VERSION 5.7 ;
  NOWIREEXTENSIONATPIN ON ;
  DIVIDERCHAR "/" ;
  BUSBITCHARS "[]" ;
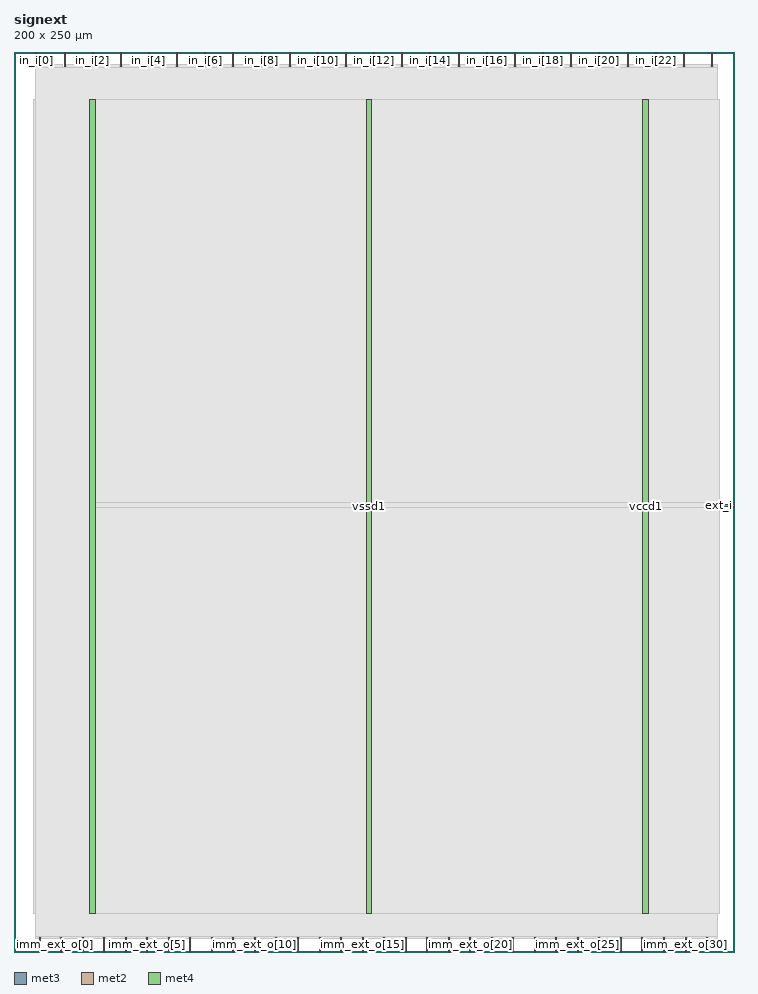
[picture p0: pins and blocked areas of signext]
MACRO signext
  CLASS BLOCK ;
  FOREIGN signext ;
  ORIGIN 0.000 0.000 ;
  SIZE 200.000 BY 250.000 ;
  PIN ext_i
    DIRECTION INPUT ;
    USE SIGNAL ;
    ANTENNAGATEAREA 0.196500 ;
    PORT
      LAYER met3 ;
        RECT 196.000 123.800 200.000 124.400 ;
    END
  END ext_i
  PIN imm_ext_o[0]
    DIRECTION OUTPUT TRISTATE ;
    USE SIGNAL ;
    ANTENNADIFFAREA 2.673000 ;
    PORT
      LAYER met2 ;
        RECT 6.990 0.000 7.270 4.000 ;
    END
  END imm_ext_o[0]
  PIN imm_ext_o[10]
    DIRECTION OUTPUT TRISTATE ;
    USE SIGNAL ;
    ANTENNADIFFAREA 2.673000 ;
    PORT
      LAYER met2 ;
        RECT 66.790 0.000 67.070 4.000 ;
    END
  END imm_ext_o[10]
  PIN imm_ext_o[11]
    DIRECTION OUTPUT TRISTATE ;
    USE SIGNAL ;
    ANTENNADIFFAREA 2.673000 ;
    PORT
      LAYER met2 ;
        RECT 72.770 0.000 73.050 4.000 ;
    END
  END imm_ext_o[11]
  PIN imm_ext_o[12]
    DIRECTION OUTPUT TRISTATE ;
    USE SIGNAL ;
    ANTENNADIFFAREA 2.673000 ;
    PORT
      LAYER met2 ;
        RECT 78.750 0.000 79.030 4.000 ;
    END
  END imm_ext_o[12]
  PIN imm_ext_o[13]
    DIRECTION OUTPUT TRISTATE ;
    USE SIGNAL ;
    ANTENNADIFFAREA 2.673000 ;
    PORT
      LAYER met2 ;
        RECT 84.730 0.000 85.010 4.000 ;
    END
  END imm_ext_o[13]
  PIN imm_ext_o[14]
    DIRECTION OUTPUT TRISTATE ;
    USE SIGNAL ;
    ANTENNADIFFAREA 2.673000 ;
    PORT
      LAYER met2 ;
        RECT 90.710 0.000 90.990 4.000 ;
    END
  END imm_ext_o[14]
  PIN imm_ext_o[15]
    DIRECTION OUTPUT TRISTATE ;
    USE SIGNAL ;
    ANTENNADIFFAREA 2.673000 ;
    PORT
      LAYER met2 ;
        RECT 96.690 0.000 96.970 4.000 ;
    END
  END imm_ext_o[15]
  PIN imm_ext_o[16]
    DIRECTION OUTPUT TRISTATE ;
    USE SIGNAL ;
    ANTENNADIFFAREA 2.673000 ;
    PORT
      LAYER met2 ;
        RECT 102.670 0.000 102.950 4.000 ;
    END
  END imm_ext_o[16]
  PIN imm_ext_o[17]
    DIRECTION OUTPUT TRISTATE ;
    USE SIGNAL ;
    ANTENNADIFFAREA 2.673000 ;
    PORT
      LAYER met2 ;
        RECT 108.650 0.000 108.930 4.000 ;
    END
  END imm_ext_o[17]
  PIN imm_ext_o[18]
    DIRECTION OUTPUT TRISTATE ;
    USE SIGNAL ;
    ANTENNADIFFAREA 2.673000 ;
    PORT
      LAYER met2 ;
        RECT 114.630 0.000 114.910 4.000 ;
    END
  END imm_ext_o[18]
  PIN imm_ext_o[19]
    DIRECTION OUTPUT TRISTATE ;
    USE SIGNAL ;
    ANTENNADIFFAREA 2.673000 ;
    PORT
      LAYER met2 ;
        RECT 120.610 0.000 120.890 4.000 ;
    END
  END imm_ext_o[19]
  PIN imm_ext_o[1]
    DIRECTION OUTPUT TRISTATE ;
    USE SIGNAL ;
    ANTENNADIFFAREA 2.673000 ;
    PORT
      LAYER met2 ;
        RECT 12.970 0.000 13.250 4.000 ;
    END
  END imm_ext_o[1]
  PIN imm_ext_o[20]
    DIRECTION OUTPUT TRISTATE ;
    USE SIGNAL ;
    ANTENNADIFFAREA 2.673000 ;
    PORT
      LAYER met2 ;
        RECT 126.590 0.000 126.870 4.000 ;
    END
  END imm_ext_o[20]
  PIN imm_ext_o[21]
    DIRECTION OUTPUT TRISTATE ;
    USE SIGNAL ;
    ANTENNADIFFAREA 2.673000 ;
    PORT
      LAYER met2 ;
        RECT 132.570 0.000 132.850 4.000 ;
    END
  END imm_ext_o[21]
  PIN imm_ext_o[22]
    DIRECTION OUTPUT TRISTATE ;
    USE SIGNAL ;
    ANTENNADIFFAREA 2.673000 ;
    PORT
      LAYER met2 ;
        RECT 138.550 0.000 138.830 4.000 ;
    END
  END imm_ext_o[22]
  PIN imm_ext_o[23]
    DIRECTION OUTPUT TRISTATE ;
    USE SIGNAL ;
    ANTENNADIFFAREA 2.673000 ;
    PORT
      LAYER met2 ;
        RECT 144.530 0.000 144.810 4.000 ;
    END
  END imm_ext_o[23]
  PIN imm_ext_o[24]
    DIRECTION OUTPUT TRISTATE ;
    USE SIGNAL ;
    ANTENNADIFFAREA 2.673000 ;
    PORT
      LAYER met2 ;
        RECT 150.510 0.000 150.790 4.000 ;
    END
  END imm_ext_o[24]
  PIN imm_ext_o[25]
    DIRECTION OUTPUT TRISTATE ;
    USE SIGNAL ;
    ANTENNADIFFAREA 2.673000 ;
    PORT
      LAYER met2 ;
        RECT 156.490 0.000 156.770 4.000 ;
    END
  END imm_ext_o[25]
  PIN imm_ext_o[26]
    DIRECTION OUTPUT TRISTATE ;
    USE SIGNAL ;
    ANTENNADIFFAREA 2.673000 ;
    PORT
      LAYER met2 ;
        RECT 162.470 0.000 162.750 4.000 ;
    END
  END imm_ext_o[26]
  PIN imm_ext_o[27]
    DIRECTION OUTPUT TRISTATE ;
    USE SIGNAL ;
    ANTENNADIFFAREA 2.673000 ;
    PORT
      LAYER met2 ;
        RECT 168.450 0.000 168.730 4.000 ;
    END
  END imm_ext_o[27]
  PIN imm_ext_o[28]
    DIRECTION OUTPUT TRISTATE ;
    USE SIGNAL ;
    ANTENNADIFFAREA 2.673000 ;
    PORT
      LAYER met2 ;
        RECT 174.430 0.000 174.710 4.000 ;
    END
  END imm_ext_o[28]
  PIN imm_ext_o[29]
    DIRECTION OUTPUT TRISTATE ;
    USE SIGNAL ;
    ANTENNADIFFAREA 2.673000 ;
    PORT
      LAYER met2 ;
        RECT 180.410 0.000 180.690 4.000 ;
    END
  END imm_ext_o[29]
  PIN imm_ext_o[2]
    DIRECTION OUTPUT TRISTATE ;
    USE SIGNAL ;
    ANTENNADIFFAREA 2.673000 ;
    PORT
      LAYER met2 ;
        RECT 18.950 0.000 19.230 4.000 ;
    END
  END imm_ext_o[2]
  PIN imm_ext_o[30]
    DIRECTION OUTPUT TRISTATE ;
    USE SIGNAL ;
    ANTENNADIFFAREA 2.673000 ;
    PORT
      LAYER met2 ;
        RECT 186.390 0.000 186.670 4.000 ;
    END
  END imm_ext_o[30]
  PIN imm_ext_o[31]
    DIRECTION OUTPUT TRISTATE ;
    USE SIGNAL ;
    ANTENNADIFFAREA 2.673000 ;
    PORT
      LAYER met2 ;
        RECT 192.370 0.000 192.650 4.000 ;
    END
  END imm_ext_o[31]
  PIN imm_ext_o[3]
    DIRECTION OUTPUT TRISTATE ;
    USE SIGNAL ;
    ANTENNADIFFAREA 2.673000 ;
    PORT
      LAYER met2 ;
        RECT 24.930 0.000 25.210 4.000 ;
    END
  END imm_ext_o[3]
  PIN imm_ext_o[4]
    DIRECTION OUTPUT TRISTATE ;
    USE SIGNAL ;
    ANTENNADIFFAREA 2.673000 ;
    PORT
      LAYER met2 ;
        RECT 30.910 0.000 31.190 4.000 ;
    END
  END imm_ext_o[4]
  PIN imm_ext_o[5]
    DIRECTION OUTPUT TRISTATE ;
    USE SIGNAL ;
    ANTENNADIFFAREA 2.673000 ;
    PORT
      LAYER met2 ;
        RECT 36.890 0.000 37.170 4.000 ;
    END
  END imm_ext_o[5]
  PIN imm_ext_o[6]
    DIRECTION OUTPUT TRISTATE ;
    USE SIGNAL ;
    ANTENNADIFFAREA 2.673000 ;
    PORT
      LAYER met2 ;
        RECT 42.870 0.000 43.150 4.000 ;
    END
  END imm_ext_o[6]
  PIN imm_ext_o[7]
    DIRECTION OUTPUT TRISTATE ;
    USE SIGNAL ;
    ANTENNADIFFAREA 2.673000 ;
    PORT
      LAYER met2 ;
        RECT 48.850 0.000 49.130 4.000 ;
    END
  END imm_ext_o[7]
  PIN imm_ext_o[8]
    DIRECTION OUTPUT TRISTATE ;
    USE SIGNAL ;
    ANTENNADIFFAREA 2.673000 ;
    PORT
      LAYER met2 ;
        RECT 54.830 0.000 55.110 4.000 ;
    END
  END imm_ext_o[8]
  PIN imm_ext_o[9]
    DIRECTION OUTPUT TRISTATE ;
    USE SIGNAL ;
    ANTENNADIFFAREA 2.673000 ;
    PORT
      LAYER met2 ;
        RECT 60.810 0.000 61.090 4.000 ;
    END
  END imm_ext_o[9]
  PIN imm_size_i[0]
    DIRECTION INPUT ;
    USE SIGNAL ;
    ANTENNAGATEAREA 0.213000 ;
    PORT
      LAYER met2 ;
        RECT 185.930 246.000 186.210 250.000 ;
    END
  END imm_size_i[0]
  PIN imm_size_i[1]
    DIRECTION INPUT ;
    USE SIGNAL ;
    ANTENNAGATEAREA 0.213000 ;
    PORT
      LAYER met2 ;
        RECT 193.750 246.000 194.030 250.000 ;
    END
  END imm_size_i[1]
  PIN in_i[0]
    DIRECTION INPUT ;
    USE SIGNAL ;
    ANTENNAGATEAREA 0.196500 ;
    PORT
      LAYER met2 ;
        RECT 6.070 246.000 6.350 250.000 ;
    END
  END in_i[0]
  PIN in_i[10]
    DIRECTION INPUT ;
    USE SIGNAL ;
    ANTENNAGATEAREA 0.196500 ;
    PORT
      LAYER met2 ;
        RECT 84.270 246.000 84.550 250.000 ;
    END
  END in_i[10]
  PIN in_i[11]
    DIRECTION INPUT ;
    USE SIGNAL ;
    ANTENNAGATEAREA 0.196500 ;
    PORT
      LAYER met2 ;
        RECT 92.090 246.000 92.370 250.000 ;
    END
  END in_i[11]
  PIN in_i[12]
    DIRECTION INPUT ;
    USE SIGNAL ;
    ANTENNAGATEAREA 0.213000 ;
    PORT
      LAYER met2 ;
        RECT 99.910 246.000 100.190 250.000 ;
    END
  END in_i[12]
  PIN in_i[13]
    DIRECTION INPUT ;
    USE SIGNAL ;
    ANTENNAGATEAREA 0.196500 ;
    PORT
      LAYER met2 ;
        RECT 107.730 246.000 108.010 250.000 ;
    END
  END in_i[13]
  PIN in_i[14]
    DIRECTION INPUT ;
    USE SIGNAL ;
    ANTENNAGATEAREA 0.196500 ;
    PORT
      LAYER met2 ;
        RECT 115.550 246.000 115.830 250.000 ;
    END
  END in_i[14]
  PIN in_i[15]
    DIRECTION INPUT ;
    USE SIGNAL ;
    ANTENNAGATEAREA 0.126000 ;
    PORT
      LAYER met2 ;
        RECT 123.370 246.000 123.650 250.000 ;
    END
  END in_i[15]
  PIN in_i[16]
    DIRECTION INPUT ;
    USE SIGNAL ;
    ANTENNAGATEAREA 0.196500 ;
    PORT
      LAYER met2 ;
        RECT 131.190 246.000 131.470 250.000 ;
    END
  END in_i[16]
  PIN in_i[17]
    DIRECTION INPUT ;
    USE SIGNAL ;
    ANTENNAGATEAREA 0.196500 ;
    PORT
      LAYER met2 ;
        RECT 139.010 246.000 139.290 250.000 ;
    END
  END in_i[17]
  PIN in_i[18]
    DIRECTION INPUT ;
    USE SIGNAL ;
    ANTENNAGATEAREA 0.196500 ;
    PORT
      LAYER met2 ;
        RECT 146.830 246.000 147.110 250.000 ;
    END
  END in_i[18]
  PIN in_i[19]
    DIRECTION INPUT ;
    USE SIGNAL ;
    ANTENNAGATEAREA 0.196500 ;
    PORT
      LAYER met2 ;
        RECT 154.650 246.000 154.930 250.000 ;
    END
  END in_i[19]
  PIN in_i[1]
    DIRECTION INPUT ;
    USE SIGNAL ;
    ANTENNAGATEAREA 0.196500 ;
    PORT
      LAYER met2 ;
        RECT 13.890 246.000 14.170 250.000 ;
    END
  END in_i[1]
  PIN in_i[20]
    DIRECTION INPUT ;
    USE SIGNAL ;
    ANTENNAGATEAREA 0.196500 ;
    PORT
      LAYER met2 ;
        RECT 162.470 246.000 162.750 250.000 ;
    END
  END in_i[20]
  PIN in_i[21]
    DIRECTION INPUT ;
    USE SIGNAL ;
    ANTENNAGATEAREA 0.196500 ;
    PORT
      LAYER met2 ;
        RECT 170.290 246.000 170.570 250.000 ;
    END
  END in_i[21]
  PIN in_i[22]
    DIRECTION INPUT ;
    USE SIGNAL ;
    ANTENNAGATEAREA 0.213000 ;
    PORT
      LAYER met2 ;
        RECT 178.110 246.000 178.390 250.000 ;
    END
  END in_i[22]
  PIN in_i[2]
    DIRECTION INPUT ;
    USE SIGNAL ;
    ANTENNAGATEAREA 0.196500 ;
    PORT
      LAYER met2 ;
        RECT 21.710 246.000 21.990 250.000 ;
    END
  END in_i[2]
  PIN in_i[3]
    DIRECTION INPUT ;
    USE SIGNAL ;
    ANTENNAGATEAREA 0.196500 ;
    PORT
      LAYER met2 ;
        RECT 29.530 246.000 29.810 250.000 ;
    END
  END in_i[3]
  PIN in_i[4]
    DIRECTION INPUT ;
    USE SIGNAL ;
    ANTENNAGATEAREA 0.196500 ;
    PORT
      LAYER met2 ;
        RECT 37.350 246.000 37.630 250.000 ;
    END
  END in_i[4]
  PIN in_i[5]
    DIRECTION INPUT ;
    USE SIGNAL ;
    ANTENNAGATEAREA 0.196500 ;
    PORT
      LAYER met2 ;
        RECT 45.170 246.000 45.450 250.000 ;
    END
  END in_i[5]
  PIN in_i[6]
    DIRECTION INPUT ;
    USE SIGNAL ;
    ANTENNAGATEAREA 0.196500 ;
    PORT
      LAYER met2 ;
        RECT 52.990 246.000 53.270 250.000 ;
    END
  END in_i[6]
  PIN in_i[7]
    DIRECTION INPUT ;
    USE SIGNAL ;
    ANTENNAGATEAREA 0.196500 ;
    PORT
      LAYER met2 ;
        RECT 60.810 246.000 61.090 250.000 ;
    END
  END in_i[7]
  PIN in_i[8]
    DIRECTION INPUT ;
    USE SIGNAL ;
    ANTENNAGATEAREA 0.196500 ;
    PORT
      LAYER met2 ;
        RECT 68.630 246.000 68.910 250.000 ;
    END
  END in_i[8]
  PIN in_i[9]
    DIRECTION INPUT ;
    USE SIGNAL ;
    ANTENNAGATEAREA 0.196500 ;
    PORT
      LAYER met2 ;
        RECT 76.450 246.000 76.730 250.000 ;
    END
  END in_i[9]
  PIN vccd1
    DIRECTION INOUT ;
    USE POWER ;
    PORT
      LAYER met4 ;
        RECT 21.040 10.640 22.640 236.880 ;
    END
    PORT
      LAYER met4 ;
        RECT 174.640 10.640 176.240 236.880 ;
    END
  END vccd1
  PIN vssd1
    DIRECTION INOUT ;
    USE GROUND ;
    PORT
      LAYER met4 ;
        RECT 97.840 10.640 99.440 236.880 ;
    END
  END vssd1
  OBS
      LAYER nwell ;
        RECT 5.330 235.225 194.310 236.830 ;
        RECT 5.330 229.785 194.310 232.615 ;
        RECT 5.330 224.345 194.310 227.175 ;
        RECT 5.330 218.905 194.310 221.735 ;
        RECT 5.330 213.465 194.310 216.295 ;
        RECT 5.330 208.025 194.310 210.855 ;
        RECT 5.330 202.585 194.310 205.415 ;
        RECT 5.330 197.145 194.310 199.975 ;
        RECT 5.330 191.705 194.310 194.535 ;
        RECT 5.330 186.265 194.310 189.095 ;
        RECT 5.330 180.825 194.310 183.655 ;
        RECT 5.330 175.385 194.310 178.215 ;
        RECT 5.330 169.945 194.310 172.775 ;
        RECT 5.330 164.505 194.310 167.335 ;
        RECT 5.330 159.065 194.310 161.895 ;
        RECT 5.330 153.625 194.310 156.455 ;
        RECT 5.330 148.185 194.310 151.015 ;
        RECT 5.330 142.745 194.310 145.575 ;
        RECT 5.330 137.305 194.310 140.135 ;
        RECT 5.330 131.865 194.310 134.695 ;
        RECT 5.330 126.425 194.310 129.255 ;
        RECT 5.330 120.985 194.310 123.815 ;
        RECT 5.330 115.545 194.310 118.375 ;
        RECT 5.330 110.105 194.310 112.935 ;
        RECT 5.330 104.665 194.310 107.495 ;
        RECT 5.330 99.225 194.310 102.055 ;
        RECT 5.330 93.785 194.310 96.615 ;
        RECT 5.330 88.345 194.310 91.175 ;
        RECT 5.330 82.905 194.310 85.735 ;
        RECT 5.330 77.465 194.310 80.295 ;
        RECT 5.330 72.025 194.310 74.855 ;
        RECT 5.330 66.585 194.310 69.415 ;
        RECT 5.330 61.145 194.310 63.975 ;
        RECT 5.330 55.705 194.310 58.535 ;
        RECT 5.330 50.265 194.310 53.095 ;
        RECT 5.330 44.825 194.310 47.655 ;
        RECT 5.330 39.385 194.310 42.215 ;
        RECT 5.330 33.945 194.310 36.775 ;
        RECT 5.330 28.505 194.310 31.335 ;
        RECT 5.330 23.065 194.310 25.895 ;
        RECT 5.330 17.625 194.310 20.455 ;
        RECT 5.330 12.185 194.310 15.015 ;
      LAYER li1 ;
        RECT 5.520 10.795 194.120 236.725 ;
      LAYER met1 ;
        RECT 5.520 10.640 195.430 236.880 ;
      LAYER met2 ;
        RECT 6.630 245.720 13.610 246.570 ;
        RECT 14.450 245.720 21.430 246.570 ;
        RECT 22.270 245.720 29.250 246.570 ;
        RECT 30.090 245.720 37.070 246.570 ;
        RECT 37.910 245.720 44.890 246.570 ;
        RECT 45.730 245.720 52.710 246.570 ;
        RECT 53.550 245.720 60.530 246.570 ;
        RECT 61.370 245.720 68.350 246.570 ;
        RECT 69.190 245.720 76.170 246.570 ;
        RECT 77.010 245.720 83.990 246.570 ;
        RECT 84.830 245.720 91.810 246.570 ;
        RECT 92.650 245.720 99.630 246.570 ;
        RECT 100.470 245.720 107.450 246.570 ;
        RECT 108.290 245.720 115.270 246.570 ;
        RECT 116.110 245.720 123.090 246.570 ;
        RECT 123.930 245.720 130.910 246.570 ;
        RECT 131.750 245.720 138.730 246.570 ;
        RECT 139.570 245.720 146.550 246.570 ;
        RECT 147.390 245.720 154.370 246.570 ;
        RECT 155.210 245.720 162.190 246.570 ;
        RECT 163.030 245.720 170.010 246.570 ;
        RECT 170.850 245.720 177.830 246.570 ;
        RECT 178.670 245.720 185.650 246.570 ;
        RECT 186.490 245.720 193.470 246.570 ;
        RECT 194.310 245.720 195.410 246.570 ;
        RECT 6.080 4.280 195.410 245.720 ;
        RECT 6.080 3.670 6.710 4.280 ;
        RECT 7.550 3.670 12.690 4.280 ;
        RECT 13.530 3.670 18.670 4.280 ;
        RECT 19.510 3.670 24.650 4.280 ;
        RECT 25.490 3.670 30.630 4.280 ;
        RECT 31.470 3.670 36.610 4.280 ;
        RECT 37.450 3.670 42.590 4.280 ;
        RECT 43.430 3.670 48.570 4.280 ;
        RECT 49.410 3.670 54.550 4.280 ;
        RECT 55.390 3.670 60.530 4.280 ;
        RECT 61.370 3.670 66.510 4.280 ;
        RECT 67.350 3.670 72.490 4.280 ;
        RECT 73.330 3.670 78.470 4.280 ;
        RECT 79.310 3.670 84.450 4.280 ;
        RECT 85.290 3.670 90.430 4.280 ;
        RECT 91.270 3.670 96.410 4.280 ;
        RECT 97.250 3.670 102.390 4.280 ;
        RECT 103.230 3.670 108.370 4.280 ;
        RECT 109.210 3.670 114.350 4.280 ;
        RECT 115.190 3.670 120.330 4.280 ;
        RECT 121.170 3.670 126.310 4.280 ;
        RECT 127.150 3.670 132.290 4.280 ;
        RECT 133.130 3.670 138.270 4.280 ;
        RECT 139.110 3.670 144.250 4.280 ;
        RECT 145.090 3.670 150.230 4.280 ;
        RECT 151.070 3.670 156.210 4.280 ;
        RECT 157.050 3.670 162.190 4.280 ;
        RECT 163.030 3.670 168.170 4.280 ;
        RECT 169.010 3.670 174.150 4.280 ;
        RECT 174.990 3.670 180.130 4.280 ;
        RECT 180.970 3.670 186.110 4.280 ;
        RECT 186.950 3.670 192.090 4.280 ;
        RECT 192.930 3.670 195.410 4.280 ;
      LAYER met3 ;
        RECT 21.050 124.800 196.000 236.805 ;
        RECT 21.050 123.400 195.600 124.800 ;
        RECT 21.050 10.715 196.000 123.400 ;
  END
END signext
END LIBRARY

